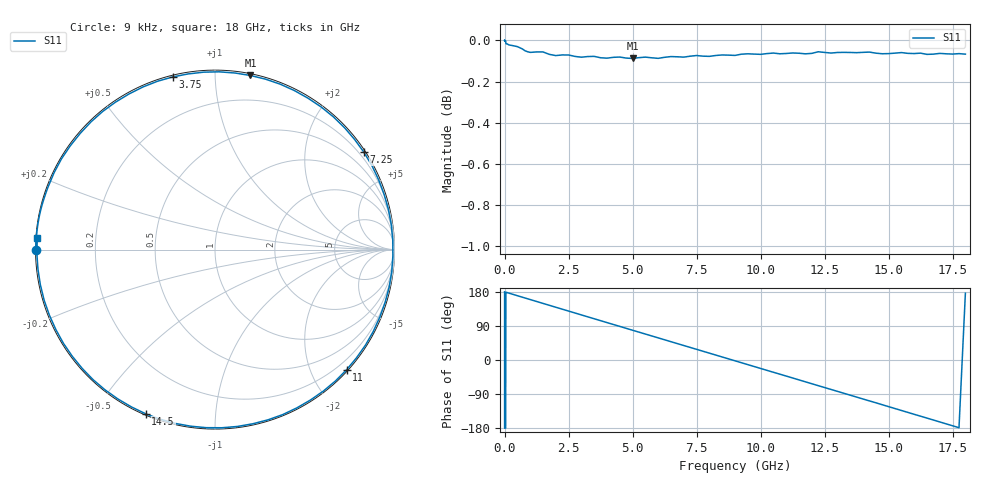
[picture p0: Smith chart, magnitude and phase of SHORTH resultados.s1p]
#	HZ	S	MA	R	50.00
! Rohde & Schwarz Vector Network Analyzer
! Rohde-Schwarz,ZNB43-2Port,1334333092101683,4.21
! Created: UTC 09/15/2026, 11:47:42 AM
! freq[Hz]	mag:S12	ang:S12
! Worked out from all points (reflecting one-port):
!   116 points, 9 kHz to 18 GHz, reference 50 ohm
!   lowest |S11| = -0.1 dB at 5 GHz (marker M1), VSWR 198.48, Z = 0.629 + j61.2 ohm
!   phase of S11 starts at 180 deg and turns -364 deg over the sweep
!   S11 on the Smith chart (normalised r, x): 9 kHz: -0.00, +0.00; 3.75 GHz: 0.01, +0.78; 7.25 GHz: 0.05, +3.36; 11 GHz: 0.03, -2.58; 14.5 GHz: 0.01, -0.66; 18 GHz: 0.00, +0.03
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9000  1 180.0
4e7  0.9997 180.5
5e7  0.9984 178.9
6e8  0.9959 167.6
1.25e9  0.9936 154.4
1.75e9  0.9922 144.3
2.5e9  0.9919 129.1
3.25e9  0.991 113.9
3.75e9  0.9904 103.8
4.25e9  0.9906 93.7
4.75e9  0.9902 83.6
5e9  0.99 78.5
6e9  0.99 58.4
7e9  0.9907 38.2
7.25e9  0.9912 33.2
8.25e9  0.9916 13.0
9.25e9  0.9923 -7.2
1e10  0.9923 -22.3
1.1e10  0.9927 -42.4
1.15e10  0.9929 -52.5
1.225e10  0.9937 -67.7
1.275e10  0.993 -77.7
1.375e10  0.9932 -97.9
1.45e10  0.9929 -112.9
1.525e10  0.9929 -128.1
1.6e10  0.9927 -143.3
1.7e10  0.9928 -163.5
1.8e10  0.9924 176.2
